One B-rep face of a CAD part: STEP entity #3673.
In plain terms, the planar face has unit normal (0, -1, 0).
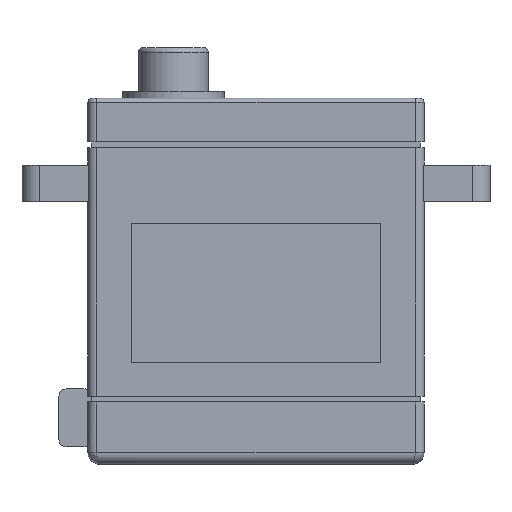
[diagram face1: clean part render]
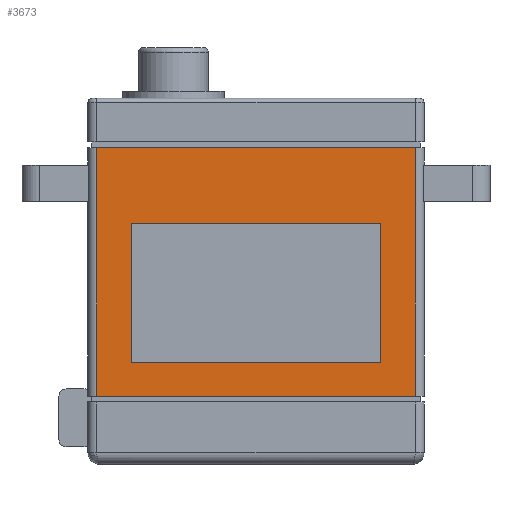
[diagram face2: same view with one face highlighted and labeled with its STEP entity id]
Its self-contained STEP definition (entity closure, numbers rounded to 3 decimals):
#959 = PLANE('',#960);
#960 = AXIS2_PLACEMENT_3D('',#961,#962,#963);
#961 = CARTESIAN_POINT('',(-6.9,-7.05,-20.55));
#962 = DIRECTION('',(0.,0.,1.));
#963 = DIRECTION('',(1.,0.,-0.));
#2564 = VERTEX_POINT('',#2565);
#2565 = CARTESIAN_POINT('',(-5.3,-6.05,-20.55));
#2580 = CYLINDRICAL_SURFACE('',#2581,0.6);
#2581 = AXIS2_PLACEMENT_3D('',#2582,#2583,#2584);
#2582 = CARTESIAN_POINT('',(-5.3,-5.45,-25.25));
#2583 = DIRECTION('',(0.,0.,1.));
#2584 = DIRECTION('',(-1.,-0.,0.));
#2592 = EDGE_CURVE('',#2564,#2593,#2595,.T.);
#2593 = VERTEX_POINT('',#2594);
#2594 = CARTESIAN_POINT('',(16.7,-6.05,-20.55));
#2595 = SURFACE_CURVE('',#2596,(#2600,#2606),.PCURVE_S1.);
#2596 = LINE('',#2597,#2598);
#2597 = CARTESIAN_POINT('',(-6.4,-6.05,-20.55));
#2598 = VECTOR('',#2599,1.);
#2599 = DIRECTION('',(1.,0.,-0.));
#2600 = PCURVE('',#959,#2601);
#2601 = DEFINITIONAL_REPRESENTATION('',(#2602),#2605);
#2602 = B_SPLINE_CURVE_WITH_KNOTS('',1,(#2603,#2604),.UNSPECIFIED.,.F.,
  .F.,(2,2),(1.1,23.1),.PIECEWISE_BEZIER_KNOTS.);
#2603 = CARTESIAN_POINT('',(1.6,1.));
#2604 = CARTESIAN_POINT('',(23.6,1.));
#2605 = ( GEOMETRIC_REPRESENTATION_CONTEXT(2) 
PARAMETRIC_REPRESENTATION_CONTEXT() REPRESENTATION_CONTEXT('2D SPACE',''
  ) );
#2606 = PCURVE('',#2607,#2612);
#2607 = PLANE('',#2608);
#2608 = AXIS2_PLACEMENT_3D('',#2609,#2610,#2611);
#2609 = CARTESIAN_POINT('',(-5.9,-6.05,-25.25));
#2610 = DIRECTION('',(-0.,1.,0.));
#2611 = DIRECTION('',(0.,0.,1.));
#2612 = DEFINITIONAL_REPRESENTATION('',(#2613),#2616);
#2613 = B_SPLINE_CURVE_WITH_KNOTS('',1,(#2614,#2615),.UNSPECIFIED.,.F.,
  .F.,(2,2),(1.1,23.1),.PIECEWISE_BEZIER_KNOTS.);
#2614 = CARTESIAN_POINT('',(4.7,0.6));
#2615 = CARTESIAN_POINT('',(4.7,22.6));
#2616 = ( GEOMETRIC_REPRESENTATION_CONTEXT(2) 
PARAMETRIC_REPRESENTATION_CONTEXT() REPRESENTATION_CONTEXT('2D SPACE',''
  ) );
#2635 = CYLINDRICAL_SURFACE('',#2636,0.6);
#2636 = AXIS2_PLACEMENT_3D('',#2637,#2638,#2639);
#2637 = CARTESIAN_POINT('',(16.7,-5.45,-25.25));
#2638 = DIRECTION('',(0.,0.,1.));
#2639 = DIRECTION('',(1.,0.,-0.));
#3180 = PLANE('',#3181);
#3181 = AXIS2_PLACEMENT_3D('',#3182,#3183,#3184);
#3182 = CARTESIAN_POINT('',(-6.9,-7.05,-3.4));
#3183 = DIRECTION('',(0.,0.,1.));
#3184 = DIRECTION('',(1.,0.,-0.));
#3532 = EDGE_CURVE('',#2593,#3533,#3535,.T.);
#3533 = VERTEX_POINT('',#3534);
#3534 = CARTESIAN_POINT('',(16.7,-6.05,-3.4));
#3535 = SURFACE_CURVE('',#3536,(#3540,#3547),.PCURVE_S1.);
#3536 = LINE('',#3537,#3538);
#3537 = CARTESIAN_POINT('',(16.7,-6.05,-25.25));
#3538 = VECTOR('',#3539,1.);
#3539 = DIRECTION('',(0.,0.,1.));
#3540 = PCURVE('',#2635,#3541);
#3541 = DEFINITIONAL_REPRESENTATION('',(#3542),#3546);
#3542 = LINE('',#3543,#3544);
#3543 = CARTESIAN_POINT('',(-1.571,0.));
#3544 = VECTOR('',#3545,1.);
#3545 = DIRECTION('',(-0.,1.));
#3546 = ( GEOMETRIC_REPRESENTATION_CONTEXT(2) 
PARAMETRIC_REPRESENTATION_CONTEXT() REPRESENTATION_CONTEXT('2D SPACE',''
  ) );
#3547 = PCURVE('',#2607,#3548);
#3548 = DEFINITIONAL_REPRESENTATION('',(#3549),#3553);
#3549 = LINE('',#3550,#3551);
#3550 = CARTESIAN_POINT('',(0.,22.6));
#3551 = VECTOR('',#3552,1.);
#3552 = DIRECTION('',(1.,0.));
#3553 = ( GEOMETRIC_REPRESENTATION_CONTEXT(2) 
PARAMETRIC_REPRESENTATION_CONTEXT() REPRESENTATION_CONTEXT('2D SPACE',''
  ) );
#3673 = ADVANCED_FACE('',(#3674,#3720),#2607,.F.);
#3674 = FACE_BOUND('',#3675,.F.);
#3675 = EDGE_LOOP('',(#3676,#3677,#3678,#3701));
#3676 = ORIENTED_EDGE('',*,*,#3532,.F.);
#3677 = ORIENTED_EDGE('',*,*,#2592,.F.);
#3678 = ORIENTED_EDGE('',*,*,#3679,.T.);
#3679 = EDGE_CURVE('',#2564,#3680,#3682,.T.);
#3680 = VERTEX_POINT('',#3681);
#3681 = CARTESIAN_POINT('',(-5.3,-6.05,-3.4));
#3682 = SURFACE_CURVE('',#3683,(#3687,#3694),.PCURVE_S1.);
#3683 = LINE('',#3684,#3685);
#3684 = CARTESIAN_POINT('',(-5.3,-6.05,-25.25));
#3685 = VECTOR('',#3686,1.);
#3686 = DIRECTION('',(0.,0.,1.));
#3687 = PCURVE('',#2607,#3688);
#3688 = DEFINITIONAL_REPRESENTATION('',(#3689),#3693);
#3689 = LINE('',#3690,#3691);
#3690 = CARTESIAN_POINT('',(0.,0.6));
#3691 = VECTOR('',#3692,1.);
#3692 = DIRECTION('',(1.,0.));
#3693 = ( GEOMETRIC_REPRESENTATION_CONTEXT(2) 
PARAMETRIC_REPRESENTATION_CONTEXT() REPRESENTATION_CONTEXT('2D SPACE',''
  ) );
#3694 = PCURVE('',#2580,#3695);
#3695 = DEFINITIONAL_REPRESENTATION('',(#3696),#3700);
#3696 = LINE('',#3697,#3698);
#3697 = CARTESIAN_POINT('',(1.571,0.));
#3698 = VECTOR('',#3699,1.);
#3699 = DIRECTION('',(0.,1.));
#3700 = ( GEOMETRIC_REPRESENTATION_CONTEXT(2) 
PARAMETRIC_REPRESENTATION_CONTEXT() REPRESENTATION_CONTEXT('2D SPACE',''
  ) );
#3701 = ORIENTED_EDGE('',*,*,#3702,.T.);
#3702 = EDGE_CURVE('',#3680,#3533,#3703,.T.);
#3703 = SURFACE_CURVE('',#3704,(#3708,#3714),.PCURVE_S1.);
#3704 = LINE('',#3705,#3706);
#3705 = CARTESIAN_POINT('',(-6.4,-6.05,-3.4));
#3706 = VECTOR('',#3707,1.);
#3707 = DIRECTION('',(1.,0.,-0.));
#3708 = PCURVE('',#2607,#3709);
#3709 = DEFINITIONAL_REPRESENTATION('',(#3710),#3713);
#3710 = B_SPLINE_CURVE_WITH_KNOTS('',1,(#3711,#3712),.UNSPECIFIED.,.F.,
  .F.,(2,2),(1.1,23.1),.PIECEWISE_BEZIER_KNOTS.);
#3711 = CARTESIAN_POINT('',(21.85,0.6));
#3712 = CARTESIAN_POINT('',(21.85,22.6));
#3713 = ( GEOMETRIC_REPRESENTATION_CONTEXT(2) 
PARAMETRIC_REPRESENTATION_CONTEXT() REPRESENTATION_CONTEXT('2D SPACE',''
  ) );
#3714 = PCURVE('',#3180,#3715);
#3715 = DEFINITIONAL_REPRESENTATION('',(#3716),#3719);
#3716 = B_SPLINE_CURVE_WITH_KNOTS('',1,(#3717,#3718),.UNSPECIFIED.,.F.,
  .F.,(2,2),(1.1,23.1),.PIECEWISE_BEZIER_KNOTS.);
#3717 = CARTESIAN_POINT('',(1.6,1.));
#3718 = CARTESIAN_POINT('',(23.6,1.));
#3719 = ( GEOMETRIC_REPRESENTATION_CONTEXT(2) 
PARAMETRIC_REPRESENTATION_CONTEXT() REPRESENTATION_CONTEXT('2D SPACE',''
  ) );
#3720 = FACE_BOUND('',#3721,.F.);
#3721 = EDGE_LOOP('',(#3722,#3750,#3776,#3802));
#3722 = ORIENTED_EDGE('',*,*,#3723,.F.);
#3723 = EDGE_CURVE('',#3724,#3726,#3728,.T.);
#3724 = VERTEX_POINT('',#3725);
#3725 = CARTESIAN_POINT('',(-2.9,-6.05,-8.6));
#3726 = VERTEX_POINT('',#3727);
#3727 = CARTESIAN_POINT('',(14.3,-6.05,-8.6));
#3728 = SURFACE_CURVE('',#3729,(#3733,#3739),.PCURVE_S1.);
#3729 = LINE('',#3730,#3731);
#3730 = CARTESIAN_POINT('',(-4.4,-6.05,-8.6));
#3731 = VECTOR('',#3732,1.);
#3732 = DIRECTION('',(1.,0.,-0.));
#3733 = PCURVE('',#2607,#3734);
#3734 = DEFINITIONAL_REPRESENTATION('',(#3735),#3738);
#3735 = B_SPLINE_CURVE_WITH_KNOTS('',1,(#3736,#3737),.UNSPECIFIED.,.F.,
  .F.,(2,2),(1.5,18.7),.PIECEWISE_BEZIER_KNOTS.);
#3736 = CARTESIAN_POINT('',(16.65,3.));
#3737 = CARTESIAN_POINT('',(16.65,20.2));
#3738 = ( GEOMETRIC_REPRESENTATION_CONTEXT(2) 
PARAMETRIC_REPRESENTATION_CONTEXT() REPRESENTATION_CONTEXT('2D SPACE',''
  ) );
#3739 = PCURVE('',#3740,#3745);
#3740 = PLANE('',#3741);
#3741 = AXIS2_PLACEMENT_3D('',#3742,#3743,#3744);
#3742 = CARTESIAN_POINT('',(-2.9,-7.05,-8.6));
#3743 = DIRECTION('',(0.,0.,1.));
#3744 = DIRECTION('',(1.,0.,-0.));
#3745 = DEFINITIONAL_REPRESENTATION('',(#3746),#3749);
#3746 = B_SPLINE_CURVE_WITH_KNOTS('',1,(#3747,#3748),.UNSPECIFIED.,.F.,
  .F.,(2,2),(1.5,18.7),.PIECEWISE_BEZIER_KNOTS.);
#3747 = CARTESIAN_POINT('',(0.,1.));
#3748 = CARTESIAN_POINT('',(17.2,1.));
#3749 = ( GEOMETRIC_REPRESENTATION_CONTEXT(2) 
PARAMETRIC_REPRESENTATION_CONTEXT() REPRESENTATION_CONTEXT('2D SPACE',''
  ) );
#3750 = ORIENTED_EDGE('',*,*,#3751,.T.);
#3751 = EDGE_CURVE('',#3724,#3752,#3754,.T.);
#3752 = VERTEX_POINT('',#3753);
#3753 = CARTESIAN_POINT('',(-2.9,-6.05,-18.25));
#3754 = SURFACE_CURVE('',#3755,(#3759,#3765),.PCURVE_S1.);
#3755 = LINE('',#3756,#3757);
#3756 = CARTESIAN_POINT('',(-2.9,-6.05,-21.75));
#3757 = VECTOR('',#3758,1.);
#3758 = DIRECTION('',(-0.,0.,-1.));
#3759 = PCURVE('',#2607,#3760);
#3760 = DEFINITIONAL_REPRESENTATION('',(#3761),#3764);
#3761 = B_SPLINE_CURVE_WITH_KNOTS('',1,(#3762,#3763),.UNSPECIFIED.,.F.,
  .F.,(2,2),(-13.15,-3.5),.PIECEWISE_BEZIER_KNOTS.);
#3762 = CARTESIAN_POINT('',(16.65,3.));
#3763 = CARTESIAN_POINT('',(7.,3.));
#3764 = ( GEOMETRIC_REPRESENTATION_CONTEXT(2) 
PARAMETRIC_REPRESENTATION_CONTEXT() REPRESENTATION_CONTEXT('2D SPACE',''
  ) );
#3765 = PCURVE('',#3766,#3771);
#3766 = PLANE('',#3767);
#3767 = AXIS2_PLACEMENT_3D('',#3768,#3769,#3770);
#3768 = CARTESIAN_POINT('',(-2.9,-7.05,-18.25));
#3769 = DIRECTION('',(1.,0.,-0.));
#3770 = DIRECTION('',(0.,0.,1.));
#3771 = DEFINITIONAL_REPRESENTATION('',(#3772),#3775);
#3772 = B_SPLINE_CURVE_WITH_KNOTS('',1,(#3773,#3774),.UNSPECIFIED.,.F.,
  .F.,(2,2),(-13.15,-3.5),.PIECEWISE_BEZIER_KNOTS.);
#3773 = CARTESIAN_POINT('',(9.65,-1.));
#3774 = CARTESIAN_POINT('',(0.,-1.));
#3775 = ( GEOMETRIC_REPRESENTATION_CONTEXT(2) 
PARAMETRIC_REPRESENTATION_CONTEXT() REPRESENTATION_CONTEXT('2D SPACE',''
  ) );
#3776 = ORIENTED_EDGE('',*,*,#3777,.T.);
#3777 = EDGE_CURVE('',#3752,#3778,#3780,.T.);
#3778 = VERTEX_POINT('',#3779);
#3779 = CARTESIAN_POINT('',(14.3,-6.05,-18.25));
#3780 = SURFACE_CURVE('',#3781,(#3785,#3791),.PCURVE_S1.);
#3781 = LINE('',#3782,#3783);
#3782 = CARTESIAN_POINT('',(-4.4,-6.05,-18.25));
#3783 = VECTOR('',#3784,1.);
#3784 = DIRECTION('',(1.,0.,-0.));
#3785 = PCURVE('',#2607,#3786);
#3786 = DEFINITIONAL_REPRESENTATION('',(#3787),#3790);
#3787 = B_SPLINE_CURVE_WITH_KNOTS('',1,(#3788,#3789),.UNSPECIFIED.,.F.,
  .F.,(2,2),(1.5,18.7),.PIECEWISE_BEZIER_KNOTS.);
#3788 = CARTESIAN_POINT('',(7.,3.));
#3789 = CARTESIAN_POINT('',(7.,20.2));
#3790 = ( GEOMETRIC_REPRESENTATION_CONTEXT(2) 
PARAMETRIC_REPRESENTATION_CONTEXT() REPRESENTATION_CONTEXT('2D SPACE',''
  ) );
#3791 = PCURVE('',#3792,#3797);
#3792 = PLANE('',#3793);
#3793 = AXIS2_PLACEMENT_3D('',#3794,#3795,#3796);
#3794 = CARTESIAN_POINT('',(-2.9,-7.05,-18.25));
#3795 = DIRECTION('',(0.,0.,1.));
#3796 = DIRECTION('',(1.,0.,-0.));
#3797 = DEFINITIONAL_REPRESENTATION('',(#3798),#3801);
#3798 = B_SPLINE_CURVE_WITH_KNOTS('',1,(#3799,#3800),.UNSPECIFIED.,.F.,
  .F.,(2,2),(1.5,18.7),.PIECEWISE_BEZIER_KNOTS.);
#3799 = CARTESIAN_POINT('',(0.,1.));
#3800 = CARTESIAN_POINT('',(17.2,1.));
#3801 = ( GEOMETRIC_REPRESENTATION_CONTEXT(2) 
PARAMETRIC_REPRESENTATION_CONTEXT() REPRESENTATION_CONTEXT('2D SPACE',''
  ) );
#3802 = ORIENTED_EDGE('',*,*,#3803,.F.);
#3803 = EDGE_CURVE('',#3726,#3778,#3804,.T.);
#3804 = SURFACE_CURVE('',#3805,(#3809,#3815),.PCURVE_S1.);
#3805 = LINE('',#3806,#3807);
#3806 = CARTESIAN_POINT('',(14.3,-6.05,-21.75));
#3807 = VECTOR('',#3808,1.);
#3808 = DIRECTION('',(-0.,0.,-1.));
#3809 = PCURVE('',#2607,#3810);
#3810 = DEFINITIONAL_REPRESENTATION('',(#3811),#3814);
#3811 = B_SPLINE_CURVE_WITH_KNOTS('',1,(#3812,#3813),.UNSPECIFIED.,.F.,
  .F.,(2,2),(-13.15,-3.5),.PIECEWISE_BEZIER_KNOTS.);
#3812 = CARTESIAN_POINT('',(16.65,20.2));
#3813 = CARTESIAN_POINT('',(7.,20.2));
#3814 = ( GEOMETRIC_REPRESENTATION_CONTEXT(2) 
PARAMETRIC_REPRESENTATION_CONTEXT() REPRESENTATION_CONTEXT('2D SPACE',''
  ) );
#3815 = PCURVE('',#3816,#3821);
#3816 = PLANE('',#3817);
#3817 = AXIS2_PLACEMENT_3D('',#3818,#3819,#3820);
#3818 = CARTESIAN_POINT('',(14.3,-7.05,-18.25));
#3819 = DIRECTION('',(1.,0.,-0.));
#3820 = DIRECTION('',(0.,0.,1.));
#3821 = DEFINITIONAL_REPRESENTATION('',(#3822),#3825);
#3822 = B_SPLINE_CURVE_WITH_KNOTS('',1,(#3823,#3824),.UNSPECIFIED.,.F.,
  .F.,(2,2),(-13.15,-3.5),.PIECEWISE_BEZIER_KNOTS.);
#3823 = CARTESIAN_POINT('',(9.65,-1.));
#3824 = CARTESIAN_POINT('',(0.,-1.));
#3825 = ( GEOMETRIC_REPRESENTATION_CONTEXT(2) 
PARAMETRIC_REPRESENTATION_CONTEXT() REPRESENTATION_CONTEXT('2D SPACE',''
  ) );
